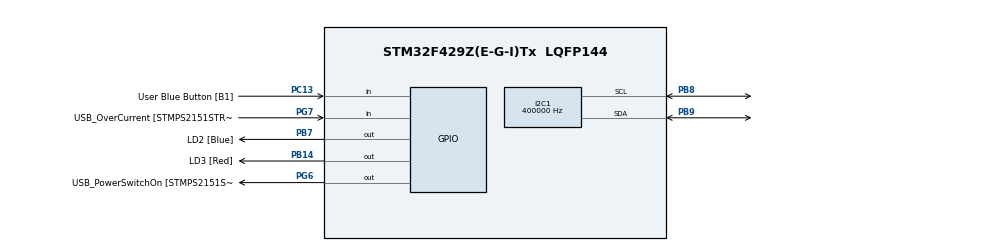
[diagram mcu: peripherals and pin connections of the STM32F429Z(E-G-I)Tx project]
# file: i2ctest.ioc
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I2C1.ClockSpeed=400000
I2C1.I2C_Mode=I2C_Fast
Mcu.Family=STM32F4
Mcu.Name=STM32F429Z(E-G-I)Tx
Mcu.Package=LQFP144
NVIC.PriorityGroup=NVIC_PRIORITYGROUP_4
PA1.GPIO_Label=RMII_REF_CLK [LAN8742A-CZ-TR_REFCLK0]
PA1.Signal=ETH_REF_CLK
PA10.GPIO_Label=USB_ID
PA10.Signal=USB_OTG_FS_ID
PA11.GPIO_Label=USB_DM
PA11.Signal=USB_OTG_FS_DM
PA12.GPIO_Label=USB_DP
PA12.Signal=USB_OTG_FS_DP
PA13.GPIO_Label=TMS
PA13.Mode=Serial_Wire
PA13.Signal=SYS_JTMS-SWDIO
PA14.GPIO_Label=TCK
PA14.Mode=Serial_Wire
PA14.Signal=SYS_JTCK-SWCLK
PA2.GPIO_Label=RMII_MDIO [LAN8742A-CZ-TR_MDIO]
PA2.Signal=ETH_MDIO
PA7.GPIO_Label=RMII_CRS_DV [LAN8742A-CZ-TR_CRS_DV]
PA7.Signal=ETH_CRS_DV
PA8.GPIO_Label=USB_SOF [TP1]
PA8.Signal=USB_OTG_FS_SOF
PA9.GPIO_Label=USB_VBUS
PA9.Signal=USB_OTG_FS_VBUS
PB13.GPIO_Label=RMII_TXD1 [LAN8742A-CZ-TR_TXD1]
PB13.Signal=ETH_TXD1
PB14.GPIO_Label=LD3 [Red]
PB14.Signal=GPIO_Output
PB7.GPIO_Label=LD2 [Blue]
PB7.Signal=GPIO_Output
PB8.Mode=I2C
PB8.Signal=I2C1_SCL
PB9.Mode=I2C
PB9.Signal=I2C1_SDA
PC1.GPIO_Label=RMII_MDC [LAN8742A-CZ-TR_MDC]
PC1.Signal=ETH_MDC
PC13.GPIO_Label=User Blue Button [B1]
PC13.Signal=GPIO_Input
PC14/OSC32_IN.Signal=RCC_OSC32_IN
PC15/OSC32_OUT.Signal=RCC_OSC32_OUT
PC4.GPIO_Label=RMII_RXD0 [LAN8742A-CZ-TR_RXD0]
PC4.Signal=ETH_RXD0
PC5.GPIO_Label=RMII_RXD1 [LAN8742A-CZ-TR_RXD1]
PC5.Signal=ETH_RXD1
PD8.GPIO_Label=STLK_RX [STM32F103CBT6_PA3]
PD8.Signal=USART3_TX
PD9.GPIO_Label=STLK_TX [STM32F103CBT6_PA2]
PD9.Signal=USART3_RX
PG11.GPIO_Label=RMII_TX_EN [LAN8742A-CZ-TR_TXEN]
PG11.Signal=ETH_TX_EN
PG13.GPIO_Label=RMII_TXD0 [LAN8742A-CZ-TR_TXD0]
PG13.Signal=ETH_TXD0
PG6.GPIO_Label=USB_PowerSwitchOn [STMPS2151STR_EN]
PG6.Signal=GPIO_Output
PG7.GPIO_Label=USB_OverCurrent [STMPS2151STR_FAULT]
PG7.Signal=GPIO_Input
PH0/OSC_IN.GPIO_Label=MCO [STM32F103CBT6_PA8]
PH0/OSC_IN.Signal=RCC_OSC_IN
PH1/OSC_OUT.Signal=RCC_OSC_OUT
ProjectManager.HeapSize=0x200
ProjectManager.StackSize=0x400
ProjectManager.TargetToolchain=SW4STM32
RCC.48MHZClocksFreq_Value=90000000
RCC.AHBFreq_Value=180000000
RCC.APB1CLKDivider=RCC_HCLK_DIV4
RCC.APB1Freq_Value=45000000
RCC.APB1TimFreq_Value=90000000
RCC.APB2CLKDivider=RCC_HCLK_DIV2
RCC.APB2Freq_Value=90000000
RCC.APB2TimFreq_Value=180000000
RCC.CortexFreq_Value=180000000
RCC.HCLKFreq_Value=180000000
RCC.HSE_VALUE=8000000
RCC.HSI_VALUE=16000000
RCC.LSE_VALUE=32768
RCC.PLLM=8
RCC.PLLMUL=RCC_PLL_MUL9
RCC.PLLN=180
RCC.PRESCALERUSB=RCC_USBCLKSOURCE_PLL_DIV1_5
RCC.SYSCLKFreq_VALUE=180000000
RCC.SYSCLKSource=RCC_SYSCLKSOURCE_PLLCLK
RCC.SYSCLKSourceVirtual=RCC_SYSCLKSOURCE_PLLCLK
RCC.USBFreq_Value=48000000
RCC.VCOOutputFreq_Value=360000000
board=NUCLEO-F429ZI

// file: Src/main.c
/**
  ******************************************************************************
  * File Name          : main.c
  * Description        : Main program body
  ******************************************************************************
  *
  * COPYRIGHT(c) 2017 STMicroelectronics
  *
  * Redistribution and use in source and binary forms, with or without modification,
  * are permitted provided that the following conditions are met:
  *   1. Redistributions of source code must retain the above copyright notice,
  *      this list of conditions and the following disclaimer.
  *   2. Redistributions in binary form must reproduce the above copyright notice,
  *      this list of conditions and the following disclaimer in the documentation
  *      and/or other materials provided with the distribution.
  *   3. Neither the name of STMicroelectronics nor the names of its contributors
  *      may be used to endorse or promote products derived from this software
  *      without specific prior written permission.
  *
  * THIS SOFTWARE IS PROVIDED BY THE COPYRIGHT HOLDERS AND CONTRIBUTORS "AS IS"
  * AND ANY EXPRESS OR IMPLIED WARRANTIES, INCLUDING, BUT NOT LIMITED TO, THE
  * IMPLIED WARRANTIES OF MERCHANTABILITY AND FITNESS FOR A PARTICULAR PURPOSE ARE
  * DISCLAIMED. IN NO EVENT SHALL THE COPYRIGHT HOLDER OR CONTRIBUTORS BE LIABLE
  * FOR ANY DIRECT, INDIRECT, INCIDENTAL, SPECIAL, EXEMPLARY, OR CONSEQUENTIAL
  * DAMAGES (INCLUDING, BUT NOT LIMITED TO, PROCUREMENT OF SUBSTITUTE GOODS OR
  * SERVICES; LOSS OF USE, DATA, OR PROFITS; OR BUSINESS INTERRUPTION) HOWEVER
  * CAUSED AND ON ANY THEORY OF LIABILITY, WHETHER IN CONTRACT, STRICT LIABILITY,
  * OR TORT (INCLUDING NEGLIGENCE OR OTHERWISE) ARISING IN ANY WAY OUT OF THE USE
  * OF THIS SOFTWARE, EVEN IF ADVISED OF THE POSSIBILITY OF SUCH DAMAGE.
  *
  ******************************************************************************
  */
#include "main.h"
#include "imu.h"
#include "stm32f4xx_hal.h"

I2C_HandleTypeDef hi2c1;

/* USER CODE BEGIN PV */
/* Private variables ---------------------------------------------------------*/

/* USER CODE END PV */

void SystemClock_Config(void);
void Error_Handler(void);
static void MX_GPIO_Init(void);
static void MX_I2C1_Init(void);

/* USER CODE BEGIN PFP */
/* Private function prototypes -----------------------------------------------*/

/* USER CODE END PFP */

/* USER CODE BEGIN 0 */
extern void initialise_monitor_handles(void);
/* USER CODE END 0 */

int main(void)
{
  initialise_monitor_handles();

  /* MCU Configuration----------------------------------------------------------*/

  /* Reset of all peripherals, Initializes the Flash interface and the Systick. */
  HAL_Init();

  /* Configure the system clock */
  SystemClock_Config();

  /* Initialize all configured peripherals */
  MX_GPIO_Init();
  MX_I2C1_Init();

  /* Infinite loop */
  /* USER CODE BEGIN WHILE */
  ImuInit(&hi2c1);
  printf("ImuInit() complete\n");

  while (1) {
	  ImuLoop();
  }
  /* USER CODE END 3 */

}

/** System Clock Configuration
*/
void SystemClock_Config(void)
{

  RCC_OscInitTypeDef RCC_OscInitStruct;
  RCC_ClkInitTypeDef RCC_ClkInitStruct;

    /**Configure the main internal regulator output voltage
    */
  __HAL_RCC_PWR_CLK_ENABLE();

  __HAL_PWR_VOLTAGESCALING_CONFIG(PWR_REGULATOR_VOLTAGE_SCALE1);

    /**Initializes the CPU, AHB and APB busses clocks
    */
  RCC_OscInitStruct.OscillatorType = RCC_OSCILLATORTYPE_HSI;
  RCC_OscInitStruct.HSIState = RCC_HSI_ON;
  RCC_OscInitStruct.HSICalibrationValue = 16;
  RCC_OscInitStruct.PLL.PLLState = RCC_PLL_ON;
  RCC_OscInitStruct.PLL.PLLSource = RCC_PLLSOURCE_HSI;
  RCC_OscInitStruct.PLL.PLLM = 8;
  RCC_OscInitStruct.PLL.PLLN = 160;
  RCC_OscInitStruct.PLL.PLLP = RCC_PLLP_DIV2;
  RCC_OscInitStruct.PLL.PLLQ = 4;
  if (HAL_RCC_OscConfig(&RCC_OscInitStruct) != HAL_OK)
  {
    Error_Handler();
  }

    /**Activate the Over-Drive mode
    */
  if (HAL_PWREx_EnableOverDrive() != HAL_OK)
  {
    Error_Handler();
  }

    /**Initializes the CPU, AHB and APB busses clocks
    */
  RCC_ClkInitStruct.ClockType = RCC_CLOCKTYPE_HCLK|RCC_CLOCKTYPE_SYSCLK
                              |RCC_CLOCKTYPE_PCLK1|RCC_CLOCKTYPE_PCLK2;
  RCC_ClkInitStruct.SYSCLKSource = RCC_SYSCLKSOURCE_PLLCLK;
  RCC_ClkInitStruct.AHBCLKDivider = RCC_SYSCLK_DIV1;
  RCC_ClkInitStruct.APB1CLKDivider = RCC_HCLK_DIV4;
  RCC_ClkInitStruct.APB2CLKDivider = RCC_HCLK_DIV2;

  if (HAL_RCC_ClockConfig(&RCC_ClkInitStruct, FLASH_LATENCY_5) != HAL_OK)
  {
    Error_Handler();
  }

    /**Configure the Systick interrupt time
    */
  HAL_SYSTICK_Config(HAL_RCC_GetHCLKFreq()/1000);

    /**Configure the Systick
    */
  HAL_SYSTICK_CLKSourceConfig(SYSTICK_CLKSOURCE_HCLK);

  /* SysTick_IRQn interrupt configuration */
  HAL_NVIC_SetPriority(SysTick_IRQn, 0, 0);
}

/* I2C1 init function */
static void MX_I2C1_Init(void)
{

  hi2c1.Instance = I2C1;
  hi2c1.Init.ClockSpeed = 400000;
  hi2c1.Init.DutyCycle = I2C_DUTYCYCLE_2;
  hi2c1.Init.OwnAddress1 = 0;
  hi2c1.Init.AddressingMode = I2C_ADDRESSINGMODE_7BIT;
  hi2c1.Init.DualAddressMode = I2C_DUALADDRESS_DISABLE;
  hi2c1.Init.OwnAddress2 = 0;
  hi2c1.Init.GeneralCallMode = I2C_GENERALCALL_DISABLE;
  hi2c1.Init.NoStretchMode = I2C_NOSTRETCH_DISABLE;
  if (HAL_I2C_Init(&hi2c1) != HAL_OK)
  {
    Error_Handler();
  }

}

/** Configure pins as
        * Analog
        * Input
        * Output
        * EVENT_OUT
        * EXTI
     PC1   ------> ETH_MDC
     PA1   ------> ETH_REF_CLK
     PA2   ------> ETH_MDIO
     PA7   ------> ETH_CRS_DV
     PC4   ------> ETH_RXD0
     PC5   ------> ETH_RXD1
     PB13   ------> ETH_TXD1
     PD8   ------> USART3_TX
     PD9   ------> USART3_RX
     PA8   ------> USB_OTG_FS_SOF
     PA9   ------> USB_OTG_FS_VBUS
     PA10   ------> USB_OTG_FS_ID
     PA11   ------> USB_OTG_FS_DM
     PA12   ------> USB_OTG_FS_DP
     PG11   ------> ETH_TX_EN
     PG13   ------> ETH_TXD0
*/
static void MX_GPIO_Init(void)
{

  GPIO_InitTypeDef GPIO_InitStruct;

  /* GPIO Ports Clock Enable */
  __HAL_RCC_GPIOC_CLK_ENABLE();
  __HAL_RCC_GPIOH_CLK_ENABLE();
  __HAL_RCC_GPIOA_CLK_ENABLE();
  __HAL_RCC_GPIOB_CLK_ENABLE();
  __HAL_RCC_GPIOD_CLK_ENABLE();
  __HAL_RCC_GPIOG_CLK_ENABLE();

  /*Configure GPIO pin : User_Blue_Button_Pin */
  GPIO_InitStruct.Pin = User_Blue_Button_Pin;
  GPIO_InitStruct.Mode = GPIO_MODE_INPUT;
  GPIO_InitStruct.Pull = GPIO_NOPULL;
  HAL_GPIO_Init(User_Blue_Button_GPIO_Port, &GPIO_InitStruct);

  /*Configure GPIO pins : RMII_MDC_Pin RMII_RXD0_Pin RMII_RXD1_Pin */
  GPIO_InitStruct.Pin = RMII_MDC_Pin|RMII_RXD0_Pin|RMII_RXD1_Pin;
  GPIO_InitStruct.Mode = GPIO_MODE_AF_PP;
  GPIO_InitStruct.Pull = GPIO_NOPULL;
  GPIO_InitStruct.Speed = GPIO_SPEED_FREQ_VERY_HIGH;
  GPIO_InitStruct.Alternate = GPIO_AF11_ETH;
  HAL_GPIO_Init(GPIOC, &GPIO_InitStruct);

  /*Configure GPIO pins : RMII_REF_CLK_Pin RMII_MDIO_Pin RMII_CRS_DV_Pin */
  GPIO_InitStruct.Pin = RMII_REF_CLK_Pin|RMII_MDIO_Pin|RMII_CRS_DV_Pin;
  GPIO_InitStruct.Mode = GPIO_MODE_AF_PP;
  GPIO_InitStruct.Pull = GPIO_NOPULL;
  GPIO_InitStruct.Speed = GPIO_SPEED_FREQ_VERY_HIGH;
  GPIO_InitStruct.Alternate = GPIO_AF11_ETH;
  HAL_GPIO_Init(GPIOA, &GPIO_InitStruct);

  /*Configure GPIO pin : RMII_TXD1_Pin */
  GPIO_InitStruct.Pin = RMII_TXD1_Pin;
  GPIO_InitStruct.Mode = GPIO_MODE_AF_PP;
  GPIO_InitStruct.Pull = GPIO_NOPULL;
  GPIO_InitStruct.Speed = GPIO_SPEED_FREQ_VERY_HIGH;
  GPIO_InitStruct.Alternate = GPIO_AF11_ETH;
  HAL_GPIO_Init(RMII_TXD1_GPIO_Port, &GPIO_InitStruct);

  /*Configure GPIO pins : LD3_Pin LD2_Pin */
  GPIO_InitStruct.Pin = LD3_Pin|LD2_Pin;
  GPIO_InitStruct.Mode = GPIO_MODE_OUTPUT_PP;
  GPIO_InitStruct.Pull = GPIO_NOPULL;
  GPIO_InitStruct.Speed = GPIO_SPEED_FREQ_LOW;
  HAL_GPIO_Init(GPIOB, &GPIO_InitStruct);

  /*Configure GPIO pins : STLK_RX_Pin STLK_TX_Pin */
  GPIO_InitStruct.Pin = STLK_RX_Pin|STLK_TX_Pin;
  GPIO_InitStruct.Mode = GPIO_MODE_AF_PP;
  GPIO_InitStruct.Pull = GPIO_NOPULL;
  GPIO_InitStruct.Speed = GPIO_SPEED_FREQ_VERY_HIGH;
  GPIO_InitStruct.Alternate = GPIO_AF7_USART3;
  HAL_GPIO_Init(GPIOD, &GPIO_InitStruct);

  /*Configure GPIO pin : USB_PowerSwitchOn_Pin */
  GPIO_InitStruct.Pin = USB_PowerSwitchOn_Pin;
  GPIO_InitStruct.Mode = GPIO_MODE_OUTPUT_PP;
  GPIO_InitStruct.Pull = GPIO_NOPULL;
  GPIO_InitStruct.Speed = GPIO_SPEED_FREQ_LOW;
  HAL_GPIO_Init(USB_PowerSwitchOn_GPIO_Port, &GPIO_InitStruct);

  /*Configure GPIO pin : USB_OverCurrent_Pin */
  GPIO_InitStruct.Pin = USB_OverCurrent_Pin;
  GPIO_InitStruct.Mode = GPIO_MODE_INPUT;
  GPIO_InitStruct.Pull = GPIO_NOPULL;
  HAL_GPIO_Init(USB_OverCurrent_GPIO_Port, &GPIO_InitStruct);

  /*Configure GPIO pins : USB_SOF_Pin USB_ID_Pin USB_DM_Pin USB_DP_Pin */
  GPIO_InitStruct.Pin = USB_SOF_Pin|USB_ID_Pin|USB_DM_Pin|USB_DP_Pin;
  GPIO_InitStruct.Mode = GPIO_MODE_AF_PP;
  GPIO_InitStruct.Pull = GPIO_NOPULL;
  GPIO_InitStruct.Speed = GPIO_SPEED_FREQ_VERY_HIGH;
  GPIO_InitStruct.Alternate = GPIO_AF10_OTG_FS;
  HAL_GPIO_Init(GPIOA, &GPIO_InitStruct);

  /*Configure GPIO pin : USB_VBUS_Pin */
  GPIO_InitStruct.Pin = USB_VBUS_Pin;
  GPIO_InitStruct.Mode = GPIO_MODE_INPUT;
  GPIO_InitStruct.Pull = GPIO_NOPULL;
  HAL_GPIO_Init(USB_VBUS_GPIO_Port, &GPIO_InitStruct);

  /*Configure GPIO pins : RMII_TX_EN_Pin RMII_TXD0_Pin */
  GPIO_InitStruct.Pin = RMII_TX_EN_Pin|RMII_TXD0_Pin;
  GPIO_InitStruct.Mode = GPIO_MODE_AF_PP;
  GPIO_InitStruct.Pull = GPIO_NOPULL;
  GPIO_InitStruct.Speed = GPIO_SPEED_FREQ_VERY_HIGH;
  GPIO_InitStruct.Alternate = GPIO_AF11_ETH;
  HAL_GPIO_Init(GPIOG, &GPIO_InitStruct);

  /*Configure GPIO pin Output Level */
  HAL_GPIO_WritePin(GPIOB, LD3_Pin|LD2_Pin, GPIO_PIN_RESET);

  /*Configure GPIO pin Output Level */
  HAL_GPIO_WritePin(USB_PowerSwitchOn_GPIO_Port, USB_PowerSwitchOn_Pin, GPIO_PIN_RESET);

}

void Error_Handler(void)
{
  while(1)
  {
  }
}

/************************ (C) COPYRIGHT STMicroelectronics *****END OF FILE****/
